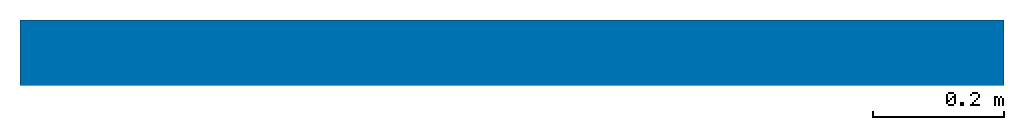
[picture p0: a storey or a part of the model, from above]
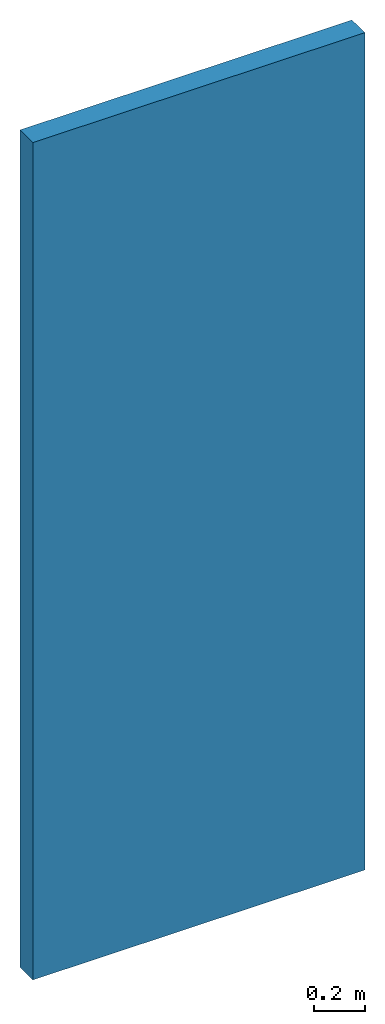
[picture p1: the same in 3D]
Properties of the parts of a building model (IFC2X3)

# File
Description: ViewDefinition [CoordinationView_V2.0]
File name: 2012C-006
Time: 2013-09-27T11:36:24
Written by: The EXPRESS Data Manager Version 5.01.0100.02.64mod : 6 Jun 2012
Made in: 20130308_1515(x64) - Exporter 3.5.0.0 - Alternate UI 2.5.0.0
Comment: STEP Physical File produced by: The EXPRESS Data Manager Version 5.01.0100.02.64mod : 6 Jun 2012 * Module: EDMstepFileFactory/EDMstandAlone * Creation date: Fri Sep 27 11:36:24 2013 * Host: MDR_LPTP_BTO * Database: C:\Users\Martijn\AppData\Local\Temp\{5A288455-243E-43FB-B77F-AB7123EB2175}\ifc * Database version: 5507 * Database creation date: Fri Sep 27 11:36:23 2013 * Schema: IFC2X3 * Model: DataRepository.ifc * Model creation date: Fri Sep 27 11:36:23 2013 * Header model: DataRepository.ifc_HeaderModel * Header model creation date: Fri Sep 27 11:36:23 2013 * EDMuser: sdai-user * EDMgroup: sdai-group * License ID and type: 5605 : Permanent license. Expiry date: * EDMstepFileFactory options: 020000

# IfcProject, 2012C-006
LongName: Dutch Revit Standards; Phase: VOORLOPIG

# IfcSite, Default
RefLatitude: 42, 24, 53, 508911; RefLongitude: -71, -15, -29, -58837; RefElevation: 0 mm

# IfcBuilding
Pset_BuildingCommon - NumberOfStoreys: 7

# IfcBuildingStorey (7)
Name | LongName | Elevation (mm)
00_begane grond | 00_begane grond | 0
01_eerste verdieping | 01_eerste verdieping | 3000
02_tweede verdieping | 02_tweede verdieping | 6000
03_derde verdieping | 03_derde verdieping | 9000
04_vierde verdieping | 04_vierde verdieping | 12000
05_vijfde verdieping | 05_vijfde verdieping | 15000
06_zesde verdieping | 06_zesde verdieping | 18000

# IfcWallStandardCase: Basic Wall:20_WA_wand_generiek_100, Basic Wall:20_WA_wand_generiek_100:317191
In: 00_begane grond
Type - PredefinedType: STANDARD; Material: 20_baksteen_wf_210x100x50_10mm_voeg_halfsteens_rood_genuanceerd 100 mm
Pset_WallCommon - Reference: 20_WA_wand_generiek_100; LoadBearing: no; ExtendToStructure: no; IsExternal: yes; FireRating: 75; ThermalTransmittance: 4.1 kg/K/s3; AcousticRating: AcousticRating; Combustible: no; Compartmentation: yes
Pset_ManufacturerTypeInformation - Manufacturer: Manufacturer; ProductionYear: ProductionYear
PSet_DRS - IfcTest: testifc
PSet_COBIE - AssetIdentifier: AssetIdentifier; BarCode: BarCode; Colour: Colour; Constituents: Constituents; Features: Features; Finish: Finish; Grade: Grade; InstallationDate: InstallationDate; Material: Material; NominalHeight: 999; NominalLength: 1500; NominalWidth: 100; ProductionYear: ProductionYear; ReplacementCost: ReplacementCost; SerialNumber: SerialNumber; ServiceLifeDuration: ServiceLifeDuration; Shape: Shape; Size: Size; TagNumber: A-01; WarrantyDescription: WarrantyDescription; WarrantyDurationLabour: WarrantyDurationLabour; WarrantyDurationParts: WarrantyDurationParts; WarrantyGuarantorLabour: WarrantyGuarantorLabour; WarrantyGuarantorParts: WarrantyGuarantorParts; WarrantyStartDate: WarrantyStartDate
